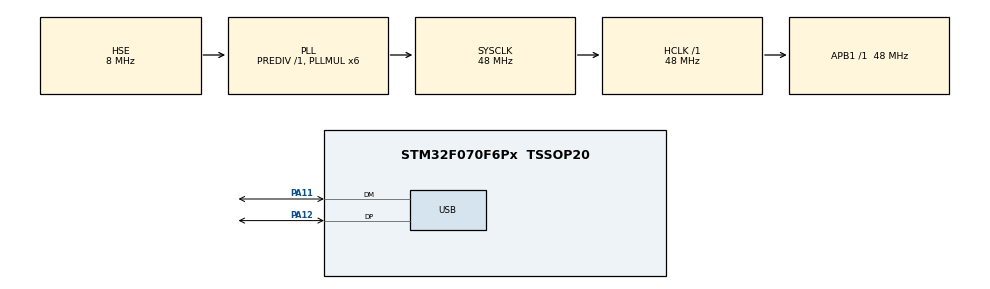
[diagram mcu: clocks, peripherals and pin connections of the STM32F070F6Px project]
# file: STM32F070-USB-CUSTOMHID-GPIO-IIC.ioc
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Mcu.Family=STM32F0
Mcu.Name=STM32F070F6Px
Mcu.Package=TSSOP20
NVIC.USB_IRQn=true\:0\:0\:false\:false\:true\:false
PA11.Mode=Device
PA11.Signal=USB_DM
PA12.Mode=Device
PA12.Signal=USB_DP
PA13.Mode=Serial_Wire
PA13.Signal=SYS_SWDIO
PA14.Mode=Serial_Wire
PA14.Signal=SYS_SWCLK
PF0-OSC_IN.Mode=HSE-External-Oscillator
PF0-OSC_IN.Signal=RCC_OSC_IN
PF1-OSC_OUT.Mode=HSE-External-Oscillator
PF1-OSC_OUT.Signal=RCC_OSC_OUT
ProjectManager.HeapSize=0x200
ProjectManager.StackSize=0x400
ProjectManager.TargetToolchain=MDK-ARM V5
RCC.AHBFreq_Value=48000000
RCC.APB1Freq_Value=48000000
RCC.APB1TimFreq_Value=48000000
RCC.HCLKFreq_Value=48000000
RCC.PLLMUL=RCC_PLL_MUL6
RCC.SYSCLKFreq_VALUE=48000000
RCC.SYSCLKSource=RCC_SYSCLKSOURCE_PLLCLK
USB_DEVICE.CLASS_NAME_FS=CUSTOMHID
USB_DEVICE.VirtualMode=CustomHid
USB_DEVICE.VirtualModeFS=Custom_Hid_FS
VP_SYS_VS_PINREMAP.Mode=PINREMAP
VP_USB_DEVICE_VS_USB_DEVICE_CUSTOM_HID_FS.Mode=CUSTOM_HID_FS
board=STM32F070-USB-CUSTOMHID-GPIO-IIC

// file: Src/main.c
/**
  ******************************************************************************
  * @file           : main.c
  * @brief          : Main program body
  ******************************************************************************
  * This notice applies to any and all portions of this file
  * that are not between comment pairs USER CODE BEGIN and
  * USER CODE END. Other portions of this file, whether
  * inserted by the user or by software development tools
  * are owned by their respective copyright owners.
  *
  * Copyright (c) 2018 STMicroelectronics International N.V.
  * All rights reserved.
  *
  * Redistribution and use in source and binary forms, with or without
  * modification, are permitted, provided that the following conditions are met:
  *
  * 1. Redistribution of source code must retain the above copyright notice,
  *    this list of conditions and the following disclaimer.
  * 2. Redistributions in binary form must reproduce the above copyright notice,
  *    this list of conditions and the following disclaimer in the documentation
  *    and/or other materials provided with the distribution.
  * 3. Neither the name of STMicroelectronics nor the names of other
  *    contributors to this software may be used to endorse or promote products
  *    derived from this software without specific written permission.
  * 4. This software, including modifications and/or derivative works of this
  *    software, must execute solely and exclusively on microcontroller or
  *    microprocessor devices manufactured by or for STMicroelectronics.
  * 5. Redistribution and use of this software other than as permitted under
  *    this license is void and will automatically terminate your rights under
  *    this license.
  *
  * THIS SOFTWARE IS PROVIDED BY STMICROELECTRONICS AND CONTRIBUTORS "AS IS"
  * AND ANY EXPRESS, IMPLIED OR STATUTORY WARRANTIES, INCLUDING, BUT NOT
  * LIMITED TO, THE IMPLIED WARRANTIES OF MERCHANTABILITY, FITNESS FOR A
  * PARTICULAR PURPOSE AND NON-INFRINGEMENT OF THIRD PARTY INTELLECTUAL PROPERTY
  * RIGHTS ARE DISCLAIMED TO THE FULLEST EXTENT PERMITTED BY LAW. IN NO EVENT
  * SHALL STMICROELECTRONICS OR CONTRIBUTORS BE LIABLE FOR ANY DIRECT, INDIRECT,
  * INCIDENTAL, SPECIAL, EXEMPLARY, OR CONSEQUENTIAL DAMAGES (INCLUDING, BUT NOT
  * LIMITED TO, PROCUREMENT OF SUBSTITUTE GOODS OR SERVICES; LOSS OF USE, DATA,
  * OR PROFITS; OR BUSINESS INTERRUPTION) HOWEVER CAUSED AND ON ANY THEORY OF
  * LIABILITY, WHETHER IN CONTRACT, STRICT LIABILITY, OR TORT (INCLUDING
  * NEGLIGENCE OR OTHERWISE) ARISING IN ANY WAY OUT OF THE USE OF THIS SOFTWARE,
  * EVEN IF ADVISED OF THE POSSIBILITY OF SUCH DAMAGE.
  *
  ******************************************************************************
  */
#include "main.h"
#include "stm32f0xx_hal.h"
#include "usb_device.h"

#include "usbd_custom_hid_if.h"

/* USER CODE BEGIN PV */
/* Private variables ---------------------------------------------------------*/

/* USER CODE END PV */

void SystemClock_Config(void);
static void MX_GPIO_Init(void);

/* USER CODE BEGIN PFP */
/* Private function prototypes -----------------------------------------------*/

/* USER CODE END PFP */

int main(void)
{

  /* MCU Configuration----------------------------------------------------------*/

  /* Reset of all peripherals, Initializes the Flash interface and the Systick. */
  HAL_Init();

  /* Configure the system clock */
  SystemClock_Config();

  /* Initialize all configured peripherals */
  MX_GPIO_Init();
  MX_USB_DEVICE_Init();

  /* Infinite loop */
  while (1)
  {
  CustomHID_ProcessOut();
  }

}

void SystemClock_Config(void)
{

  RCC_OscInitTypeDef RCC_OscInitStruct;
  RCC_ClkInitTypeDef RCC_ClkInitStruct;
  RCC_PeriphCLKInitTypeDef PeriphClkInit;

    /**Initializes the CPU, AHB and APB busses clocks
    */
  RCC_OscInitStruct.OscillatorType = RCC_OSCILLATORTYPE_HSE;
  RCC_OscInitStruct.HSEState = RCC_HSE_ON;
  RCC_OscInitStruct.PLL.PLLState = RCC_PLL_ON;
  RCC_OscInitStruct.PLL.PLLSource = RCC_PLLSOURCE_HSE;
  RCC_OscInitStruct.PLL.PLLMUL = RCC_PLL_MUL6;
  RCC_OscInitStruct.PLL.PREDIV = RCC_PREDIV_DIV1;
  if (HAL_RCC_OscConfig(&RCC_OscInitStruct) != HAL_OK)
  {
    _Error_Handler(__FILE__, __LINE__);
  }

    /**Initializes the CPU, AHB and APB busses clocks
    */
  RCC_ClkInitStruct.ClockType = RCC_CLOCKTYPE_HCLK|RCC_CLOCKTYPE_SYSCLK
                              |RCC_CLOCKTYPE_PCLK1;
  RCC_ClkInitStruct.SYSCLKSource = RCC_SYSCLKSOURCE_PLLCLK;
  RCC_ClkInitStruct.AHBCLKDivider = RCC_SYSCLK_DIV1;
  RCC_ClkInitStruct.APB1CLKDivider = RCC_HCLK_DIV1;

  if (HAL_RCC_ClockConfig(&RCC_ClkInitStruct, FLASH_LATENCY_1) != HAL_OK)
  {
    _Error_Handler(__FILE__, __LINE__);
  }

  PeriphClkInit.PeriphClockSelection = RCC_PERIPHCLK_USB;
  PeriphClkInit.UsbClockSelection = RCC_USBCLKSOURCE_PLL;

  if (HAL_RCCEx_PeriphCLKConfig(&PeriphClkInit) != HAL_OK)
  {
    _Error_Handler(__FILE__, __LINE__);
  }

    /**Configure the Systick interrupt time
    */
  HAL_SYSTICK_Config(HAL_RCC_GetHCLKFreq()/1000);

    /**Configure the Systick
    */
  HAL_SYSTICK_CLKSourceConfig(SYSTICK_CLKSOURCE_HCLK);

  /* SysTick_IRQn interrupt configuration */
  HAL_NVIC_SetPriority(SysTick_IRQn, 0, 0);
}

/** Configure pins as
        * Analog
        * Input
        * Output
        * EVENT_OUT
        * EXTI
*/
static void MX_GPIO_Init(void)
{
  GPIO_InitTypeDef GPIO_InitStruct;

  /* GPIO Ports Clock Enable */
  __HAL_RCC_GPIOF_CLK_ENABLE();
  __HAL_RCC_GPIOA_CLK_ENABLE();

  GPIO_InitStruct.Pin = GPIO_PIN_2|GPIO_PIN_3;
  GPIO_InitStruct.Mode = GPIO_MODE_OUTPUT_OD;
  GPIO_InitStruct.Pull = GPIO_NOPULL;
  GPIO_InitStruct.Speed = GPIO_SPEED_FREQ_HIGH;
  HAL_GPIO_Init(GPIOA, &GPIO_InitStruct);
  HAL_GPIO_WritePin(GPIOA, GPIO_PIN_2, GPIO_PIN_SET);
  HAL_GPIO_WritePin(GPIOA, GPIO_PIN_3, GPIO_PIN_SET);

  GPIO_InitStruct.Pin = GPIO_PIN_0|GPIO_PIN_1|GPIO_PIN_4;
  GPIO_InitStruct.Mode = GPIO_MODE_OUTPUT_PP;
  GPIO_InitStruct.Speed = GPIO_SPEED_FREQ_LOW;
  GPIO_InitStruct.Pull = GPIO_PULLDOWN;
  HAL_GPIO_Init(GPIOA, &GPIO_InitStruct);
  HAL_GPIO_WritePin(GPIOA, GPIO_PIN_0, GPIO_PIN_RESET);
  HAL_GPIO_WritePin(GPIOA, GPIO_PIN_1, GPIO_PIN_SET);
  HAL_GPIO_WritePin(GPIOA, GPIO_PIN_4, GPIO_PIN_RESET);

}

void _Error_Handler(char *file, int line)
{
  while(1)
  {
  }
}

/************************ (C) COPYRIGHT STMicroelectronics *****END OF FILE****/
